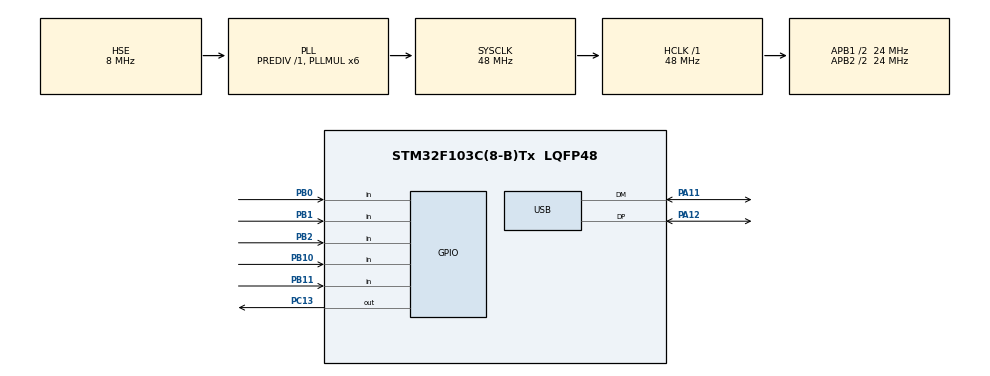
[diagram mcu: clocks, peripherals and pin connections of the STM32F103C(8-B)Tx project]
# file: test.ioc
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Mcu.Family=STM32F1
Mcu.Name=STM32F103C(8-B)Tx
Mcu.Package=LQFP48
NVIC.PriorityGroup=NVIC_PRIORITYGROUP_4
NVIC.USB_LP_CAN1_RX0_IRQn=true\:0\:0\:false\:false\:true
PA11.Mode=Device
PA11.Signal=USB_DM
PA12.Mode=Device
PA12.Signal=USB_DP
PA13.Mode=Serial_Wire
PA13.Signal=SYS_JTMS-SWDIO
PA14.Mode=Serial_Wire
PA14.Signal=SYS_JTCK-SWCLK
PB0.Signal=GPIO_Input
PB1.Signal=GPIO_Input
PB10.Signal=GPIO_Input
PB11.Signal=GPIO_Input
PB2.Signal=GPIO_Input
PC13-TAMPER-RTC.Signal=GPIO_Output
PC14-OSC32_IN.Signal=RCC_OSC32_IN
PC15-OSC32_OUT.Signal=RCC_OSC32_OUT
PD0-OSC_IN.Mode=HSE-External-Oscillator
PD0-OSC_IN.Signal=RCC_OSC_IN
PD1-OSC_OUT.Mode=HSE-External-Oscillator
PD1-OSC_OUT.Signal=RCC_OSC_OUT
ProjectManager.HeapSize=0x200
ProjectManager.StackSize=0x400
ProjectManager.TargetToolchain=TrueSTUDIO
RCC.AHBFreq_Value=48000000
RCC.APB1CLKDivider=RCC_HCLK_DIV2
RCC.APB1Freq_Value=24000000
RCC.APB1TimFreq_Value=48000000
RCC.APB2CLKDivider=RCC_HCLK_DIV2
RCC.APB2Freq_Value=24000000
RCC.APB2TimFreq_Value=48000000
RCC.HCLKFreq_Value=48000000
RCC.HSIState=RCC_HSI_ON
RCC.PLLMUL=RCC_PLL_MUL6
RCC.PLLSourceVirtual=RCC_PLLSOURCE_HSE
RCC.SYSCLKFreq_VALUE=48000000
RCC.SYSCLKSource=RCC_SYSCLKSOURCE_PLLCLK
RCC.USBFreq_Value=48000000
USB_DEVICE.USBD_HandleTypeDef=hUsbDeviceFS
USB_DEVICE.VirtualMode=Hid
USB_DEVICE.VirtualModeFS=Hid_FS
VP_USB_DEVICE_VS_USB_DEVICE_HID_FS.Mode=HID_FS
board=test

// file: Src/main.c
/**
 ******************************************************************************
 * File Name          : main.c
 * Description        : Main program body
 ******************************************************************************
 *
 * COPYRIGHT(c) 2016 STMicroelectronics
 *
 * Redistribution and use in source and binary forms, with or without modification,
 * are permitted provided that the following conditions are met:
 *   1. Redistributions of source code must retain the above copyright notice,
 *      this list of conditions and the following disclaimer.
 *   2. Redistributions in binary form must reproduce the above copyright notice,
 *      this list of conditions and the following disclaimer in the documentation
 *      and/or other materials provided with the distribution.
 *   3. Neither the name of STMicroelectronics nor the names of its contributors
 *      may be used to endorse or promote products derived from this software
 *      without specific prior written permission.
 *
 * THIS SOFTWARE IS PROVIDED BY THE COPYRIGHT HOLDERS AND CONTRIBUTORS "AS IS"
 * AND ANY EXPRESS OR IMPLIED WARRANTIES, INCLUDING, BUT NOT LIMITED TO, THE
 * IMPLIED WARRANTIES OF MERCHANTABILITY AND FITNESS FOR A PARTICULAR PURPOSE ARE
 * DISCLAIMED. IN NO EVENT SHALL THE COPYRIGHT HOLDER OR CONTRIBUTORS BE LIABLE
 * FOR ANY DIRECT, INDIRECT, INCIDENTAL, SPECIAL, EXEMPLARY, OR CONSEQUENTIAL
 * DAMAGES (INCLUDING, BUT NOT LIMITED TO, PROCUREMENT OF SUBSTITUTE GOODS OR
 * SERVICES; LOSS OF USE, DATA, OR PROFITS; OR BUSINESS INTERRUPTION) HOWEVER
 * CAUSED AND ON ANY THEORY OF LIABILITY, WHETHER IN CONTRACT, STRICT LIABILITY,
 * OR TORT (INCLUDING NEGLIGENCE OR OTHERWISE) ARISING IN ANY WAY OUT OF THE USE
 * OF THIS SOFTWARE, EVEN IF ADVISED OF THE POSSIBILITY OF SUCH DAMAGE.
 *
 ******************************************************************************
 */
#include "stm32f1xx_hal.h"
#include "usb_device.h"

/* USER CODE BEGIN Includes */
#include "usbd_hid.h"
#include "main.h"
extern USBD_HandleTypeDef hUsbDeviceFS;
/* USER CODE END Includes */

/* USER CODE BEGIN PV */
// HID Media
struct mediaHID_t {
	uint8_t id;
	uint8_t keys;
};
// HID Keyboard
struct keyboardHID_t {
	uint8_t id;
	uint8_t modifiers;
	uint8_t key1;
	uint8_t key2;
	uint8_t key3;
};
/* Private variables ---------------------------------------------------------*/
/* USER CODE END PV */

void SystemClock_Config(void);
void Error_Handler(void);
static void MX_GPIO_Init(void);
void sendMediaKey();
void sendStdKey();
void releaseStdKey();
void releaseMediaKey();
void releaseStdKey();
void releaseAllKeys();

/* USER CODE BEGIN PFP */
/* Private function prototypes -----------------------------------------------*/

/* USER CODE END PFP */

int main(void) {

	/* MCU Configuration----------------------------------------------------------*/

	/* Reset of all peripherals, Initializes the Flash interface and the Systick. */
	HAL_Init();

	/* Configure the system clock */
	SystemClock_Config();

	/* Initialize all configured peripherals */
	MX_GPIO_Init();
	MX_USB_DEVICE_Init();

	/* Infinite loop */
	while (1) {

		/* USER CODE BEGIN 3 */
		HAL_GPIO_TogglePin(GPIOC, GPIO_PIN_13);

		if (HAL_GPIO_ReadPin(GPIOB, GPIO_PIN_0) == GPIO_PIN_SET) { /// volume down
			sendMediaKey(USB_HID_VOL_DEC);
		} else if (HAL_GPIO_ReadPin(GPIOB, GPIO_PIN_1) == GPIO_PIN_SET) { ///volume up
			sendMediaKey(USB_HID_VOL_UP);
		}

		if (HAL_GPIO_ReadPin(GPIOB, GPIO_PIN_13) == GPIO_PIN_SET) { ////volume mute
			sendMediaKey(USB_HID_MUTE);
		} else if (HAL_GPIO_ReadPin(GPIOB, GPIO_PIN_10) == GPIO_PIN_SET) { ///play/pause
			sendMediaKey(USB_HID_PAUSE);
			//sendMediaKey(USB_HID_STOP);
		} else if (HAL_GPIO_ReadPin(GPIOB, GPIO_PIN_11) == GPIO_PIN_SET) { // previous
			sendMediaKey(USB_HID_SCAN_PREV);
		} else if (HAL_GPIO_ReadPin(GPIOB, GPIO_PIN_12) == GPIO_PIN_SET) { // next
			sendMediaKey(USB_HID_SCAN_NEXT);
		} else if (HAL_GPIO_ReadPin(GPIOB, GPIO_PIN_14) == GPIO_PIN_SET) { // lock screen

			sendStdKey(USB_HID_MODIFIER_LEFT_GUI, USB_HID_KEY_L, 0, 0);
			//sendStdKey(USB_HID_MODIFIER_LEFT_ALT, USB_HID_KEY_TAB, 0, 0);
		}
		while (HAL_GPIO_ReadPin(GPIOB, GPIO_PIN_13) == GPIO_PIN_SET // volume mute
		|| HAL_GPIO_ReadPin(GPIOB, GPIO_PIN_10) == GPIO_PIN_SET // play/pause
		|| HAL_GPIO_ReadPin(GPIOB, GPIO_PIN_11) == GPIO_PIN_SET // previous
		|| HAL_GPIO_ReadPin(GPIOB, GPIO_PIN_12) == GPIO_PIN_SET //next
		|| HAL_GPIO_ReadPin(GPIOB, GPIO_PIN_14) == GPIO_PIN_SET) { // lock screen
			//do nothing while some of those keys above are pressed
			HAL_GPIO_TogglePin(GPIOC, GPIO_PIN_13);
			HAL_Delay(50);
		}
		HAL_Delay(100);

	}
	/* USER CODE END 3 */

}
void sendMediaKey(int key) {
	struct mediaHID_t mediaHID;
	mediaHID.id = 2;
	mediaHID.keys = key;
	USBD_HID_SendReport(&hUsbDeviceFS, &mediaHID, sizeof(struct mediaHID_t));
	HAL_Delay(30);
	releaseMediaKey();

}
void sendStdKey(int modifier, int key1, int key2, int key3) {
	struct keyboardHID_t keyboardHID;
	keyboardHID.id = 1;
	keyboardHID.modifiers = modifier;
	keyboardHID.key1 = key1;
	keyboardHID.key2 = key2;
	keyboardHID.key3 = key3;
	USBD_HID_SendReport(&hUsbDeviceFS, &keyboardHID,
			sizeof(struct keyboardHID_t));
	HAL_Delay(30);
	releaseStdKey();

}
void releaseMediaKey() {
	struct mediaHID_t mediaHID;
		mediaHID.id = 2;
		mediaHID.keys = 0;
		USBD_HID_SendReport(&hUsbDeviceFS, &mediaHID, sizeof(struct mediaHID_t));
}
void releaseStdKey() {
	struct keyboardHID_t keyboardHID;
		keyboardHID.id = 1;
		keyboardHID.modifiers = 0;
		keyboardHID.key1 = 0;
		keyboardHID.key2 = 0;
		keyboardHID.key3 = 0;
		USBD_HID_SendReport(&hUsbDeviceFS, &keyboardHID,
				sizeof(struct keyboardHID_t));
}
void releaseAllKeys() {
	releaseStdKey();
	releaseAllKeys();

}

/** System Clock Configuration
 */
void SystemClock_Config(void) {

	RCC_OscInitTypeDef RCC_OscInitStruct;
	RCC_ClkInitTypeDef RCC_ClkInitStruct;
	RCC_PeriphCLKInitTypeDef PeriphClkInit;

	RCC_OscInitStruct.OscillatorType = RCC_OSCILLATORTYPE_HSE;
	RCC_OscInitStruct.HSEState = RCC_HSE_ON;
	RCC_OscInitStruct.HSEPredivValue = RCC_HSE_PREDIV_DIV1;
	RCC_OscInitStruct.PLL.PLLState = RCC_PLL_ON;
	RCC_OscInitStruct.PLL.PLLSource = RCC_PLLSOURCE_HSE;
	RCC_OscInitStruct.PLL.PLLMUL = RCC_PLL_MUL6;
	if (HAL_RCC_OscConfig(&RCC_OscInitStruct) != HAL_OK) {
		Error_Handler();
	}

	RCC_ClkInitStruct.ClockType = RCC_CLOCKTYPE_HCLK | RCC_CLOCKTYPE_SYSCLK
			| RCC_CLOCKTYPE_PCLK1 | RCC_CLOCKTYPE_PCLK2;
	RCC_ClkInitStruct.SYSCLKSource = RCC_SYSCLKSOURCE_PLLCLK;
	RCC_ClkInitStruct.AHBCLKDivider = RCC_SYSCLK_DIV1;
	RCC_ClkInitStruct.APB1CLKDivider = RCC_HCLK_DIV2;
	RCC_ClkInitStruct.APB2CLKDivider = RCC_HCLK_DIV2;
	if (HAL_RCC_ClockConfig(&RCC_ClkInitStruct, FLASH_LATENCY_1) != HAL_OK) {
		Error_Handler();
	}

	PeriphClkInit.PeriphClockSelection = RCC_PERIPHCLK_USB;
	PeriphClkInit.UsbClockSelection = RCC_USBCLKSOURCE_PLL;
	if (HAL_RCCEx_PeriphCLKConfig(&PeriphClkInit) != HAL_OK) {
		Error_Handler();
	}

	HAL_SYSTICK_Config(HAL_RCC_GetHCLKFreq() / 1000);

	HAL_SYSTICK_CLKSourceConfig(SYSTICK_CLKSOURCE_HCLK);

	/* SysTick_IRQn interrupt configuration */
	HAL_NVIC_SetPriority(SysTick_IRQn, 0, 0);
}

/** Configure pins as
 * Analog
 * Input
 * Output
 * EVENT_OUT
 * EXTI
 */
static void MX_GPIO_Init(void) {

	GPIO_InitTypeDef GPIO_InitStruct;

	/* GPIO Ports Clock Enable */
	__HAL_RCC_GPIOC_CLK_ENABLE()
	;
	__HAL_RCC_GPIOD_CLK_ENABLE()
	;
	__HAL_RCC_GPIOB_CLK_ENABLE()
	;
	__HAL_RCC_GPIOA_CLK_ENABLE()
	;

	/*Configure GPIO pin Output Level */
	HAL_GPIO_WritePin(GPIOC, GPIO_PIN_13, GPIO_PIN_RESET);

	/*Configure GPIO pin : PC13 */
	GPIO_InitStruct.Pin = GPIO_PIN_13;
	GPIO_InitStruct.Mode = GPIO_MODE_OUTPUT_PP;
	GPIO_InitStruct.Speed = GPIO_SPEED_FREQ_LOW;
	HAL_GPIO_Init(GPIOC, &GPIO_InitStruct);

	/*Configure GPIO pins : PB0 PB1 PB2 PB10
	 PB11 PB12 PB13 PB14*/
	GPIO_InitStruct.Pin = GPIO_PIN_0 | GPIO_PIN_1 | GPIO_PIN_2 | GPIO_PIN_10
			| GPIO_PIN_11 | GPIO_PIN_12 | GPIO_PIN_13 | GPIO_PIN_14;
	GPIO_InitStruct.Mode = GPIO_MODE_INPUT;
	GPIO_InitStruct.Pull = GPIO_PULLDOWN;
	HAL_GPIO_Init(GPIOB, &GPIO_InitStruct);

}

void Error_Handler(void) {
	/* USER CODE BEGIN Error_Handler */
	/* User can add his own implementation to report the HAL error return state */
	while (1) {
		HAL_NVIC_SystemReset();
	}
	/* USER CODE END Error_Handler */
}

/************************ (C) COPYRIGHT STMicroelectronics *****END OF FILE****/
